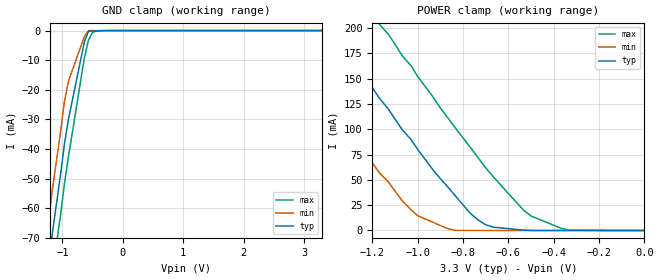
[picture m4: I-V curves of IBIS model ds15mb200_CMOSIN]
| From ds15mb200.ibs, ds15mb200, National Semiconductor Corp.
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[Model]   ds15mb200_CMOSIN
Model_type Input
Vinh=2.0
Vinl=0.8
C_comp   2pF   2pF   2pF
[Model Spec]
S_overshoot_high   3.3   3.0   3.6
S_overshoot_low   0.0   0.0   0.0
[Temperature Range]   25   85   -40
[Voltage Range]   3.3   3.0   3.6
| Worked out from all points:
|   GND clamp passes 1 mA (typ) near -0.58 V on its own axis
|   POWER clamp passes 1 mA (typ) near -0.56 V on its own axis
[GND Clamp]
-3.3V     -416mA     -402mA     -429mA
-1.3V     -89.7mA    -74.9mA    -104mA
-1.23V    -79.3mA    -64.5mA    -93mA
-1.17V    -69.1mA    -54.4mA    -82.7mA
-1.1V     -58.8mA    -44.3mA    -72.5mA
-1.03V    -48.6mA    -34.2mA    -62.2mA
-967mV    -38.4mA    -24.1mA    -51.9mA
-900mV    -30mA      -17.1mA    -42.6mA
-633mV    -3.57mA    -1.9mA     -8.92mA
-567mV    -239uA     -420nA     -3.14mA
-433mV    -133uA     -233nA     -61.9uA
3.3V      21.4pA     19.7pA     6.6nA
[POWER Clamp]
-2.47V    551mA      475mA      626mA
-1.63V    280mA      203mA      354mA
-1.6V     269mA      193mA      344mA
-1.37V    194mA      118mA      268mA
-1.17V    131mA      57.1mA     204mA
-1.13V    120mA      48mA       194mA
-1V       80mA       14.5mA     152mA
-833mV    33.9mA     60uA       101mA
-700mV    5.68mA     6.68uA     61.9mA
-533mV    372uA      1.71nA     20mA
-366mV    1.1uA      12.8pA     2.03mA
0V        6.66pA     6.3pA      6.59nA
